VERSION 5.7 ;
  NOWIREEXTENSIONATPIN ON ;
  DIVIDERCHAR "/" ;
  BUSBITCHARS "[]" ;
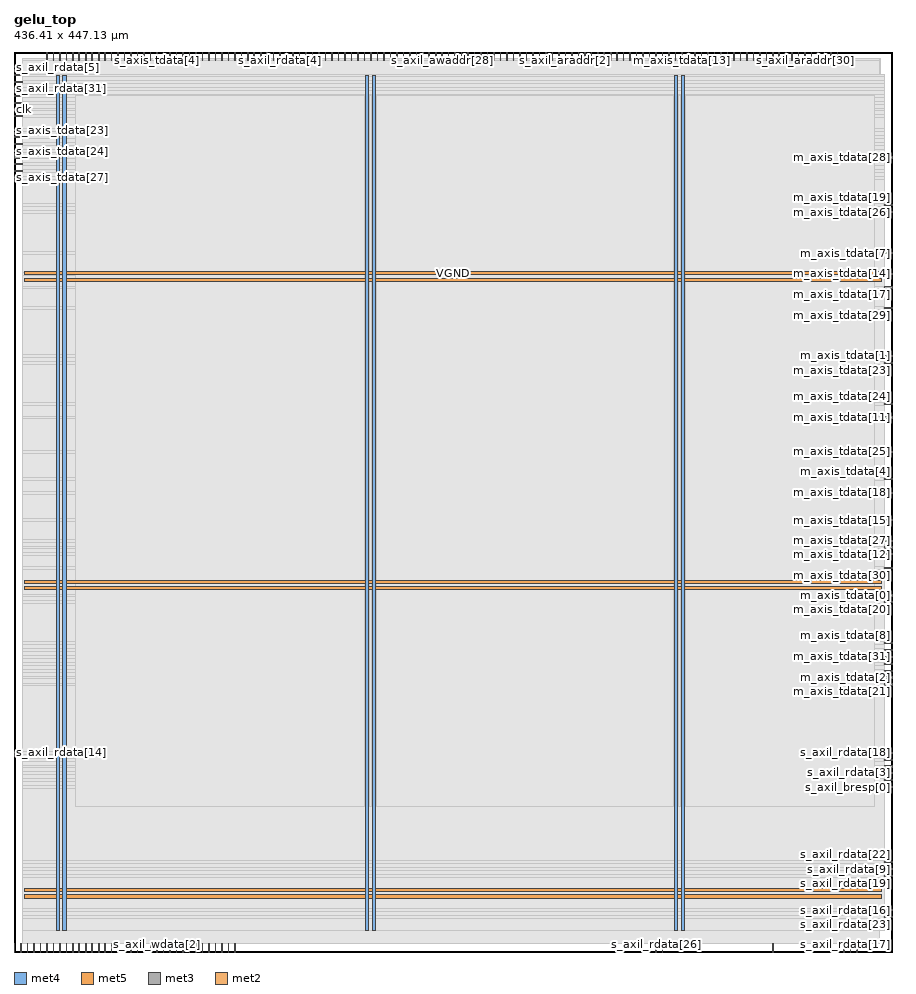
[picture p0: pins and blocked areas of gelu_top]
MACRO gelu_top
  CLASS BLOCK ;
  FOREIGN gelu_top ;
  ORIGIN 0.000 0.000 ;
  SIZE 436.410 BY 447.130 ;
  PIN VGND
    DIRECTION INOUT ;
    USE GROUND ;
    PORT
      LAYER met4 ;
        RECT 24.340 10.640 25.940 435.440 ;
    END
    PORT
      LAYER met4 ;
        RECT 177.940 10.640 179.540 435.440 ;
    END
    PORT
      LAYER met4 ;
        RECT 331.540 10.640 333.140 435.440 ;
    END
    PORT
      LAYER met5 ;
        RECT 5.280 30.030 430.800 31.630 ;
    END
    PORT
      LAYER met5 ;
        RECT 5.280 183.210 430.800 184.810 ;
    END
    PORT
      LAYER met5 ;
        RECT 5.280 336.390 430.800 337.990 ;
    END
  END VGND
  PIN VPWR
    DIRECTION INOUT ;
    USE POWER ;
    PORT
      LAYER met4 ;
        RECT 21.040 10.640 22.640 435.440 ;
    END
    PORT
      LAYER met4 ;
        RECT 174.640 10.640 176.240 435.440 ;
    END
    PORT
      LAYER met4 ;
        RECT 328.240 10.640 329.840 435.440 ;
    END
    PORT
      LAYER met5 ;
        RECT 5.280 26.730 430.800 28.330 ;
    END
    PORT
      LAYER met5 ;
        RECT 5.280 179.910 430.800 181.510 ;
    END
    PORT
      LAYER met5 ;
        RECT 5.280 333.090 430.800 334.690 ;
    END
  END VPWR
  PIN clk
    DIRECTION INPUT ;
    USE SIGNAL ;
    ANTENNAGATEAREA 0.852000 ;
    PORT
      LAYER met3 ;
        RECT 0.000 418.240 4.000 418.840 ;
    END
  END clk
  PIN m_axis_tdata[0]
    DIRECTION OUTPUT ;
    USE SIGNAL ;
    ANTENNADIFFAREA 0.445500 ;
    PORT
      LAYER met3 ;
        RECT 432.410 176.840 436.410 177.440 ;
    END
  END m_axis_tdata[0]
  PIN m_axis_tdata[10]
    DIRECTION OUTPUT ;
    USE SIGNAL ;
    ANTENNADIFFAREA 0.445500 ;
    PORT
      LAYER met2 ;
        RECT 409.030 443.130 409.310 447.130 ;
    END
  END m_axis_tdata[10]
  PIN m_axis_tdata[11]
    DIRECTION OUTPUT ;
    USE SIGNAL ;
    ANTENNADIFFAREA 0.445500 ;
    PORT
      LAYER met3 ;
        RECT 432.410 265.240 436.410 265.840 ;
    END
  END m_axis_tdata[11]
  PIN m_axis_tdata[12]
    DIRECTION OUTPUT ;
    USE SIGNAL ;
    ANTENNADIFFAREA 0.445500 ;
    PORT
      LAYER met3 ;
        RECT 432.410 197.240 436.410 197.840 ;
    END
  END m_axis_tdata[12]
  PIN m_axis_tdata[13]
    DIRECTION OUTPUT ;
    USE SIGNAL ;
    ANTENNADIFFAREA 0.445500 ;
    PORT
      LAYER met2 ;
        RECT 331.750 443.130 332.030 447.130 ;
    END
  END m_axis_tdata[13]
  PIN m_axis_tdata[14]
    DIRECTION OUTPUT ;
    USE SIGNAL ;
    ANTENNADIFFAREA 0.445500 ;
    PORT
      LAYER met3 ;
        RECT 432.410 336.640 436.410 337.240 ;
    END
  END m_axis_tdata[14]
  PIN m_axis_tdata[15]
    DIRECTION OUTPUT ;
    USE SIGNAL ;
    ANTENNADIFFAREA 0.445500 ;
    PORT
      LAYER met3 ;
        RECT 432.410 214.240 436.410 214.840 ;
    END
  END m_axis_tdata[15]
  PIN m_axis_tdata[16]
    DIRECTION OUTPUT ;
    USE SIGNAL ;
    ANTENNADIFFAREA 0.445500 ;
    PORT
      LAYER met2 ;
        RECT 322.090 443.130 322.370 447.130 ;
    END
  END m_axis_tdata[16]
  PIN m_axis_tdata[17]
    DIRECTION OUTPUT ;
    USE SIGNAL ;
    ANTENNADIFFAREA 0.445500 ;
    PORT
      LAYER met3 ;
        RECT 432.410 329.840 436.410 330.440 ;
    END
  END m_axis_tdata[17]
  PIN m_axis_tdata[18]
    DIRECTION OUTPUT ;
    USE SIGNAL ;
    ANTENNADIFFAREA 0.445500 ;
    PORT
      LAYER met3 ;
        RECT 432.410 227.840 436.410 228.440 ;
    END
  END m_axis_tdata[18]
  PIN m_axis_tdata[19]
    DIRECTION OUTPUT ;
    USE SIGNAL ;
    ANTENNADIFFAREA 0.445500 ;
    PORT
      LAYER met3 ;
        RECT 432.410 370.640 436.410 371.240 ;
    END
  END m_axis_tdata[19]
  PIN m_axis_tdata[1]
    DIRECTION OUTPUT ;
    USE SIGNAL ;
    ANTENNADIFFAREA 0.445500 ;
    PORT
      LAYER met3 ;
        RECT 432.410 295.840 436.410 296.440 ;
    END
  END m_axis_tdata[1]
  PIN m_axis_tdata[20]
    DIRECTION OUTPUT ;
    USE SIGNAL ;
    ANTENNADIFFAREA 0.445500 ;
    PORT
      LAYER met3 ;
        RECT 432.410 173.440 436.410 174.040 ;
    END
  END m_axis_tdata[20]
  PIN m_axis_tdata[21]
    DIRECTION OUTPUT ;
    USE SIGNAL ;
    ANTENNADIFFAREA 0.445500 ;
    PORT
      LAYER met3 ;
        RECT 432.410 132.640 436.410 133.240 ;
    END
  END m_axis_tdata[21]
  PIN m_axis_tdata[22]
    DIRECTION OUTPUT ;
    USE SIGNAL ;
    ANTENNADIFFAREA 0.445500 ;
    PORT
      LAYER met2 ;
        RECT 351.070 443.130 351.350 447.130 ;
    END
  END m_axis_tdata[22]
  PIN m_axis_tdata[23]
    DIRECTION OUTPUT ;
    USE SIGNAL ;
    ANTENNADIFFAREA 0.445500 ;
    PORT
      LAYER met3 ;
        RECT 432.410 292.440 436.410 293.040 ;
    END
  END m_axis_tdata[23]
  PIN m_axis_tdata[24]
    DIRECTION OUTPUT ;
    USE SIGNAL ;
    ANTENNADIFFAREA 0.445500 ;
    PORT
      LAYER met3 ;
        RECT 432.410 272.040 436.410 272.640 ;
    END
  END m_axis_tdata[24]
  PIN m_axis_tdata[25]
    DIRECTION OUTPUT ;
    USE SIGNAL ;
    ANTENNADIFFAREA 0.445500 ;
    PORT
      LAYER met3 ;
        RECT 432.410 248.240 436.410 248.840 ;
    END
  END m_axis_tdata[25]
  PIN m_axis_tdata[26]
    DIRECTION OUTPUT ;
    USE SIGNAL ;
    ANTENNADIFFAREA 0.445500 ;
    PORT
      LAYER met3 ;
        RECT 432.410 367.240 436.410 367.840 ;
    END
  END m_axis_tdata[26]
  PIN m_axis_tdata[27]
    DIRECTION OUTPUT ;
    USE SIGNAL ;
    ANTENNADIFFAREA 0.445500 ;
    PORT
      LAYER met3 ;
        RECT 432.410 200.640 436.410 201.240 ;
    END
  END m_axis_tdata[27]
  PIN m_axis_tdata[28]
    DIRECTION OUTPUT ;
    USE SIGNAL ;
    ANTENNADIFFAREA 0.445500 ;
    PORT
      LAYER met3 ;
        RECT 432.410 394.440 436.410 395.040 ;
    END
  END m_axis_tdata[28]
  PIN m_axis_tdata[29]
    DIRECTION OUTPUT ;
    USE SIGNAL ;
    ANTENNADIFFAREA 0.445500 ;
    PORT
      LAYER met3 ;
        RECT 432.410 319.640 436.410 320.240 ;
    END
  END m_axis_tdata[29]
  PIN m_axis_tdata[2]
    DIRECTION OUTPUT ;
    USE SIGNAL ;
    ANTENNADIFFAREA 0.445500 ;
    PORT
      LAYER met3 ;
        RECT 432.410 136.040 436.410 136.640 ;
    END
  END m_axis_tdata[2]
  PIN m_axis_tdata[30]
    DIRECTION OUTPUT ;
    USE SIGNAL ;
    ANTENNADIFFAREA 0.445500 ;
    PORT
      LAYER met3 ;
        RECT 432.410 190.440 436.410 191.040 ;
    END
  END m_axis_tdata[30]
  PIN m_axis_tdata[31]
    DIRECTION OUTPUT ;
    USE SIGNAL ;
    ANTENNADIFFAREA 0.445500 ;
    PORT
      LAYER met3 ;
        RECT 432.410 142.840 436.410 143.440 ;
    END
  END m_axis_tdata[31]
  PIN m_axis_tdata[3]
    DIRECTION OUTPUT ;
    USE SIGNAL ;
    ANTENNADIFFAREA 0.445500 ;
    PORT
      LAYER met3 ;
        RECT 432.410 149.640 436.410 150.240 ;
    END
  END m_axis_tdata[3]
  PIN m_axis_tdata[4]
    DIRECTION OUTPUT ;
    USE SIGNAL ;
    ANTENNADIFFAREA 0.445500 ;
    PORT
      LAYER met3 ;
        RECT 432.410 234.640 436.410 235.240 ;
    END
  END m_axis_tdata[4]
  PIN m_axis_tdata[5]
    DIRECTION OUTPUT ;
    USE SIGNAL ;
    ANTENNADIFFAREA 0.445500 ;
    PORT
      LAYER met3 ;
        RECT 432.410 204.040 436.410 204.640 ;
    END
  END m_axis_tdata[5]
  PIN m_axis_tdata[6]
    DIRECTION OUTPUT ;
    USE SIGNAL ;
    ANTENNADIFFAREA 0.445500 ;
    PORT
      LAYER met3 ;
        RECT 432.410 139.440 436.410 140.040 ;
    END
  END m_axis_tdata[6]
  PIN m_axis_tdata[7]
    DIRECTION OUTPUT ;
    USE SIGNAL ;
    ANTENNADIFFAREA 0.445500 ;
    PORT
      LAYER met3 ;
        RECT 432.410 346.840 436.410 347.440 ;
    END
  END m_axis_tdata[7]
  PIN m_axis_tdata[8]
    DIRECTION OUTPUT ;
    USE SIGNAL ;
    ANTENNADIFFAREA 0.445500 ;
    PORT
      LAYER met3 ;
        RECT 432.410 153.040 436.410 153.640 ;
    END
  END m_axis_tdata[8]
  PIN m_axis_tdata[9]
    DIRECTION OUTPUT ;
    USE SIGNAL ;
    ANTENNADIFFAREA 0.445500 ;
    PORT
      LAYER met3 ;
        RECT 432.410 146.240 436.410 146.840 ;
    END
  END m_axis_tdata[9]
  PIN m_axis_tlast
    DIRECTION OUTPUT ;
    USE SIGNAL ;
    ANTENNADIFFAREA 0.445500 ;
    PORT
      LAYER met2 ;
        RECT 357.510 443.130 357.790 447.130 ;
    END
  END m_axis_tlast
  PIN m_axis_tready
    DIRECTION INPUT ;
    USE SIGNAL ;
    ANTENNAGATEAREA 0.196500 ;
    PORT
      LAYER met2 ;
        RECT 325.310 443.130 325.590 447.130 ;
    END
  END m_axis_tready
  PIN m_axis_tuser
    DIRECTION OUTPUT ;
    USE SIGNAL ;
    ANTENNADIFFAREA 0.445500 ;
    PORT
      LAYER met2 ;
        RECT 389.710 443.130 389.990 447.130 ;
    END
  END m_axis_tuser
  PIN m_axis_tvalid
    DIRECTION OUTPUT ;
    USE SIGNAL ;
    ANTENNADIFFAREA 0.445500 ;
    PORT
      LAYER met2 ;
        RECT 270.570 443.130 270.850 447.130 ;
    END
  END m_axis_tvalid
  PIN rst
    DIRECTION INPUT ;
    USE SIGNAL ;
    ANTENNAGATEAREA 0.247500 ;
    PORT
      LAYER met3 ;
        RECT 0.000 414.840 4.000 415.440 ;
    END
  END rst
  PIN s_axil_araddr[0]
    DIRECTION INPUT ;
    USE SIGNAL ;
    ANTENNAGATEAREA 0.196500 ;
    PORT
      LAYER met2 ;
        RECT 222.270 443.130 222.550 447.130 ;
    END
  END s_axil_araddr[0]
  PIN s_axil_araddr[10]
    DIRECTION INPUT ;
    USE SIGNAL ;
    ANTENNAGATEAREA 0.196500 ;
    PORT
      LAYER met2 ;
        RECT 16.190 443.130 16.470 447.130 ;
    END
  END s_axil_araddr[10]
  PIN s_axil_araddr[11]
    DIRECTION INPUT ;
    USE SIGNAL ;
    ANTENNAGATEAREA 0.196500 ;
    PORT
      LAYER met2 ;
        RECT 141.770 443.130 142.050 447.130 ;
    END
  END s_axil_araddr[11]
  PIN s_axil_araddr[12]
    DIRECTION INPUT ;
    USE SIGNAL ;
    ANTENNAGATEAREA 0.196500 ;
    PORT
      LAYER met2 ;
        RECT 170.750 443.130 171.030 447.130 ;
    END
  END s_axil_araddr[12]
  PIN s_axil_araddr[13]
    DIRECTION INPUT ;
    USE SIGNAL ;
    ANTENNAGATEAREA 0.196500 ;
    PORT
      LAYER met2 ;
        RECT 25.850 443.130 26.130 447.130 ;
    END
  END s_axil_araddr[13]
  PIN s_axil_araddr[14]
    DIRECTION INPUT ;
    USE SIGNAL ;
    ANTENNAGATEAREA 0.196500 ;
    PORT
      LAYER met2 ;
        RECT 161.090 443.130 161.370 447.130 ;
    END
  END s_axil_araddr[14]
  PIN s_axil_araddr[15]
    DIRECTION INPUT ;
    USE SIGNAL ;
    ANTENNAGATEAREA 0.196500 ;
    PORT
      LAYER met2 ;
        RECT 138.550 443.130 138.830 447.130 ;
    END
  END s_axil_araddr[15]
  PIN s_axil_araddr[16]
    DIRECTION INPUT ;
    USE SIGNAL ;
    ANTENNAGATEAREA 0.196500 ;
    PORT
      LAYER met2 ;
        RECT 183.630 443.130 183.910 447.130 ;
    END
  END s_axil_araddr[16]
  PIN s_axil_araddr[17]
    DIRECTION INPUT ;
    USE SIGNAL ;
    ANTENNAGATEAREA 0.196500 ;
    PORT
      LAYER met2 ;
        RECT 51.610 443.130 51.890 447.130 ;
    END
  END s_axil_araddr[17]
  PIN s_axil_araddr[18]
    DIRECTION INPUT ;
    USE SIGNAL ;
    ANTENNAGATEAREA 0.196500 ;
    PORT
      LAYER met2 ;
        RECT 154.650 443.130 154.930 447.130 ;
    END
  END s_axil_araddr[18]
  PIN s_axil_araddr[19]
    DIRECTION INPUT ;
    USE SIGNAL ;
    ANTENNAGATEAREA 0.196500 ;
    PORT
      LAYER met2 ;
        RECT 151.430 443.130 151.710 447.130 ;
    END
  END s_axil_araddr[19]
  PIN s_axil_araddr[1]
    DIRECTION INPUT ;
    USE SIGNAL ;
    ANTENNAGATEAREA 0.196500 ;
    PORT
      LAYER met2 ;
        RECT 254.470 443.130 254.750 447.130 ;
    END
  END s_axil_araddr[1]
  PIN s_axil_araddr[20]
    DIRECTION INPUT ;
    USE SIGNAL ;
    ANTENNAGATEAREA 0.196500 ;
    PORT
      LAYER met2 ;
        RECT 196.510 443.130 196.790 447.130 ;
    END
  END s_axil_araddr[20]
  PIN s_axil_araddr[21]
    DIRECTION INPUT ;
    USE SIGNAL ;
    ANTENNAGATEAREA 0.196500 ;
    PORT
      LAYER met2 ;
        RECT 167.530 443.130 167.810 447.130 ;
    END
  END s_axil_araddr[21]
  PIN s_axil_araddr[22]
    DIRECTION INPUT ;
    USE SIGNAL ;
    ANTENNAGATEAREA 0.196500 ;
    PORT
      LAYER met2 ;
        RECT 376.830 443.130 377.110 447.130 ;
    END
  END s_axil_araddr[22]
  PIN s_axil_araddr[23]
    DIRECTION INPUT ;
    USE SIGNAL ;
    ANTENNAGATEAREA 0.196500 ;
    PORT
      LAYER met2 ;
        RECT 367.170 443.130 367.450 447.130 ;
    END
  END s_axil_araddr[23]
  PIN s_axil_araddr[24]
    DIRECTION INPUT ;
    USE SIGNAL ;
    ANTENNAGATEAREA 0.196500 ;
    PORT
      LAYER met2 ;
        RECT 373.610 443.130 373.890 447.130 ;
    END
  END s_axil_araddr[24]
  PIN s_axil_araddr[25]
    DIRECTION INPUT ;
    USE SIGNAL ;
    ANTENNAGATEAREA 0.126000 ;
    PORT
      LAYER met2 ;
        RECT 35.510 443.130 35.790 447.130 ;
    END
  END s_axil_araddr[25]
  PIN s_axil_araddr[26]
    DIRECTION INPUT ;
    USE SIGNAL ;
    ANTENNAGATEAREA 0.196500 ;
    PORT
      LAYER met2 ;
        RECT 186.850 443.130 187.130 447.130 ;
    END
  END s_axil_araddr[26]
  PIN s_axil_araddr[27]
    DIRECTION INPUT ;
    USE SIGNAL ;
    ANTENNAGATEAREA 0.196500 ;
    PORT
      LAYER met2 ;
        RECT 199.730 443.130 200.010 447.130 ;
    END
  END s_axil_araddr[27]
  PIN s_axil_araddr[28]
    DIRECTION INPUT ;
    USE SIGNAL ;
    ANTENNAGATEAREA 0.196500 ;
    PORT
      LAYER met2 ;
        RECT 383.270 443.130 383.550 447.130 ;
    END
  END s_axil_araddr[28]
  PIN s_axil_araddr[29]
    DIRECTION INPUT ;
    USE SIGNAL ;
    ANTENNAGATEAREA 0.196500 ;
    PORT
      LAYER met2 ;
        RECT 215.830 443.130 216.110 447.130 ;
    END
  END s_axil_araddr[29]
  PIN s_axil_araddr[2]
    DIRECTION INPUT ;
    USE SIGNAL ;
    ANTENNAGATEAREA 0.196500 ;
    PORT
      LAYER met2 ;
        RECT 273.790 443.130 274.070 447.130 ;
    END
  END s_axil_araddr[2]
  PIN s_axil_araddr[30]
    DIRECTION INPUT ;
    USE SIGNAL ;
    ANTENNAGATEAREA 0.196500 ;
    PORT
      LAYER met2 ;
        RECT 392.930 443.130 393.210 447.130 ;
    END
  END s_axil_araddr[30]
  PIN s_axil_araddr[31]
    DIRECTION INPUT ;
    USE SIGNAL ;
    ANTENNAGATEAREA 0.196500 ;
    PORT
      LAYER met2 ;
        RECT 386.490 443.130 386.770 447.130 ;
    END
  END s_axil_araddr[31]
  PIN s_axil_araddr[3]
    DIRECTION INPUT ;
    USE SIGNAL ;
    ANTENNAGATEAREA 0.196500 ;
    PORT
      LAYER met2 ;
        RECT 277.010 443.130 277.290 447.130 ;
    END
  END s_axil_araddr[3]
  PIN s_axil_araddr[4]
    DIRECTION INPUT ;
    USE SIGNAL ;
    ANTENNAGATEAREA 0.196500 ;
    PORT
      LAYER met2 ;
        RECT 128.890 443.130 129.170 447.130 ;
    END
  END s_axil_araddr[4]
  PIN s_axil_araddr[5]
    DIRECTION INPUT ;
    USE SIGNAL ;
    ANTENNAGATEAREA 0.196500 ;
    PORT
      LAYER met2 ;
        RECT 280.230 443.130 280.510 447.130 ;
    END
  END s_axil_araddr[5]
  PIN s_axil_araddr[6]
    DIRECTION INPUT ;
    USE SIGNAL ;
    ANTENNAGATEAREA 0.196500 ;
    PORT
      LAYER met2 ;
        RECT 106.350 443.130 106.630 447.130 ;
    END
  END s_axil_araddr[6]
  PIN s_axil_araddr[7]
    DIRECTION INPUT ;
    USE SIGNAL ;
    ANTENNAGATEAREA 0.196500 ;
    PORT
      LAYER met2 ;
        RECT 190.070 443.130 190.350 447.130 ;
    END
  END s_axil_araddr[7]
  PIN s_axil_araddr[8]
    DIRECTION INPUT ;
    USE SIGNAL ;
    ANTENNAGATEAREA 0.196500 ;
    PORT
      LAYER met2 ;
        RECT 193.290 443.130 193.570 447.130 ;
    END
  END s_axil_araddr[8]
  PIN s_axil_araddr[9]
    DIRECTION INPUT ;
    USE SIGNAL ;
    ANTENNAGATEAREA 0.196500 ;
    PORT
      LAYER met2 ;
        RECT 173.970 443.130 174.250 447.130 ;
    END
  END s_axil_araddr[9]
  PIN s_axil_arready
    DIRECTION OUTPUT ;
    USE SIGNAL ;
    ANTENNADIFFAREA 0.445500 ;
    PORT
      LAYER met2 ;
        RECT 251.250 443.130 251.530 447.130 ;
    END
  END s_axil_arready
  PIN s_axil_arvalid
    DIRECTION INPUT ;
    USE SIGNAL ;
    ANTENNAGATEAREA 0.196500 ;
    PORT
      LAYER met2 ;
        RECT 238.370 443.130 238.650 447.130 ;
    END
  END s_axil_arvalid
  PIN s_axil_awaddr[0]
    DIRECTION INPUT ;
    USE SIGNAL ;
    ANTENNAGATEAREA 0.196500 ;
    PORT
      LAYER met2 ;
        RECT 283.450 443.130 283.730 447.130 ;
    END
  END s_axil_awaddr[0]
  PIN s_axil_awaddr[10]
    DIRECTION INPUT ;
    USE SIGNAL ;
    ANTENNAGATEAREA 0.196500 ;
    PORT
      LAYER met2 ;
        RECT 305.990 443.130 306.270 447.130 ;
    END
  END s_axil_awaddr[10]
  PIN s_axil_awaddr[11]
    DIRECTION INPUT ;
    USE SIGNAL ;
    ANTENNAGATEAREA 0.196500 ;
    PORT
      LAYER met2 ;
        RECT 296.330 443.130 296.610 447.130 ;
    END
  END s_axil_awaddr[11]
  PIN s_axil_awaddr[12]
    DIRECTION INPUT ;
    USE SIGNAL ;
    ANTENNAGATEAREA 0.196500 ;
    PORT
      LAYER met2 ;
        RECT 219.050 443.130 219.330 447.130 ;
    END
  END s_axil_awaddr[12]
  PIN s_axil_awaddr[13]
    DIRECTION INPUT ;
    USE SIGNAL ;
    ANTENNAGATEAREA 0.196500 ;
    PORT
      LAYER met2 ;
        RECT 309.210 443.130 309.490 447.130 ;
    END
  END s_axil_awaddr[13]
  PIN s_axil_awaddr[14]
    DIRECTION INPUT ;
    USE SIGNAL ;
    ANTENNAGATEAREA 0.196500 ;
    PORT
      LAYER met2 ;
        RECT 312.430 443.130 312.710 447.130 ;
    END
  END s_axil_awaddr[14]
  PIN s_axil_awaddr[15]
    DIRECTION INPUT ;
    USE SIGNAL ;
    ANTENNAGATEAREA 0.196500 ;
    PORT
      LAYER met2 ;
        RECT 315.650 443.130 315.930 447.130 ;
    END
  END s_axil_awaddr[15]
  PIN s_axil_awaddr[16]
    DIRECTION INPUT ;
    USE SIGNAL ;
    ANTENNAGATEAREA 0.196500 ;
    PORT
      LAYER met2 ;
        RECT 318.870 443.130 319.150 447.130 ;
    END
  END s_axil_awaddr[16]
  PIN s_axil_awaddr[17]
    DIRECTION INPUT ;
    USE SIGNAL ;
    ANTENNAGATEAREA 0.196500 ;
    PORT
      LAYER met2 ;
        RECT 328.530 443.130 328.810 447.130 ;
    END
  END s_axil_awaddr[17]
  PIN s_axil_awaddr[18]
    DIRECTION INPUT ;
    USE SIGNAL ;
    ANTENNAGATEAREA 0.196500 ;
    PORT
      LAYER met2 ;
        RECT 334.970 443.130 335.250 447.130 ;
    END
  END s_axil_awaddr[18]
  PIN s_axil_awaddr[19]
    DIRECTION INPUT ;
    USE SIGNAL ;
    ANTENNAGATEAREA 0.196500 ;
    PORT
      LAYER met2 ;
        RECT 338.190 443.130 338.470 447.130 ;
    END
  END s_axil_awaddr[19]
  PIN s_axil_awaddr[1]
    DIRECTION INPUT ;
    USE SIGNAL ;
    ANTENNAGATEAREA 0.196500 ;
    PORT
      LAYER met2 ;
        RECT 241.590 443.130 241.870 447.130 ;
    END
  END s_axil_awaddr[1]
  PIN s_axil_awaddr[20]
    DIRECTION INPUT ;
    USE SIGNAL ;
    ANTENNAGATEAREA 0.196500 ;
    PORT
      LAYER met2 ;
        RECT 370.390 443.130 370.670 447.130 ;
    END
  END s_axil_awaddr[20]
  PIN s_axil_awaddr[21]
    DIRECTION INPUT ;
    USE SIGNAL ;
    ANTENNAGATEAREA 0.196500 ;
    PORT
      LAYER met2 ;
        RECT 341.410 443.130 341.690 447.130 ;
    END
  END s_axil_awaddr[21]
  PIN s_axil_awaddr[22]
    DIRECTION INPUT ;
    USE SIGNAL ;
    ANTENNAGATEAREA 0.126000 ;
    PORT
      LAYER met2 ;
        RECT 22.630 443.130 22.910 447.130 ;
    END
  END s_axil_awaddr[22]
  PIN s_axil_awaddr[23]
    DIRECTION INPUT ;
    USE SIGNAL ;
    ANTENNAGATEAREA 0.196500 ;
    PORT
      LAYER met2 ;
        RECT 209.390 443.130 209.670 447.130 ;
    END
  END s_axil_awaddr[23]
  PIN s_axil_awaddr[24]
    DIRECTION INPUT ;
    USE SIGNAL ;
    ANTENNAGATEAREA 0.196500 ;
    PORT
      LAYER met2 ;
        RECT 177.190 443.130 177.470 447.130 ;
    END
  END s_axil_awaddr[24]
  PIN s_axil_awaddr[25]
    DIRECTION INPUT ;
    USE SIGNAL ;
    ANTENNAGATEAREA 0.196500 ;
    PORT
      LAYER met2 ;
        RECT 206.170 443.130 206.450 447.130 ;
    END
  END s_axil_awaddr[25]
  PIN s_axil_awaddr[26]
    DIRECTION INPUT ;
    USE SIGNAL ;
    ANTENNAGATEAREA 0.213000 ;
    PORT
      LAYER met2 ;
        RECT 19.410 443.130 19.690 447.130 ;
    END
  END s_axil_awaddr[26]
  PIN s_axil_awaddr[27]
    DIRECTION INPUT ;
    USE SIGNAL ;
    ANTENNAGATEAREA 0.126000 ;
    PORT
      LAYER met2 ;
        RECT 396.150 443.130 396.430 447.130 ;
    END
  END s_axil_awaddr[27]
  PIN s_axil_awaddr[28]
    DIRECTION INPUT ;
    USE SIGNAL ;
    ANTENNAGATEAREA 0.196500 ;
    PORT
      LAYER met2 ;
        RECT 212.610 443.130 212.890 447.130 ;
    END
  END s_axil_awaddr[28]
  PIN s_axil_awaddr[29]
    DIRECTION INPUT ;
    USE SIGNAL ;
    ANTENNAGATEAREA 0.213000 ;
    PORT
      LAYER met2 ;
        RECT 402.590 443.130 402.870 447.130 ;
    END
  END s_axil_awaddr[29]
  PIN s_axil_awaddr[2]
    DIRECTION INPUT ;
    USE SIGNAL ;
    ANTENNAGATEAREA 0.196500 ;
    PORT
      LAYER met2 ;
        RECT 302.770 443.130 303.050 447.130 ;
    END
  END s_axil_awaddr[2]
  PIN s_axil_awaddr[30]
    DIRECTION INPUT ;
    USE SIGNAL ;
    ANTENNAGATEAREA 0.196500 ;
    PORT
      LAYER met2 ;
        RECT 380.050 443.130 380.330 447.130 ;
    END
  END s_axil_awaddr[30]
  PIN s_axil_awaddr[31]
    DIRECTION INPUT ;
    USE SIGNAL ;
    ANTENNAGATEAREA 0.196500 ;
    PORT
      LAYER met2 ;
        RECT 399.370 443.130 399.650 447.130 ;
    END
  END s_axil_awaddr[31]
  PIN s_axil_awaddr[3]
    DIRECTION INPUT ;
    USE SIGNAL ;
    ANTENNAGATEAREA 0.196500 ;
    PORT
      LAYER met2 ;
        RECT 286.670 443.130 286.950 447.130 ;
    END
  END s_axil_awaddr[3]
  PIN s_axil_awaddr[4]
    DIRECTION INPUT ;
    USE SIGNAL ;
    ANTENNAGATEAREA 0.196500 ;
    PORT
      LAYER met2 ;
        RECT 344.630 443.130 344.910 447.130 ;
    END
  END s_axil_awaddr[4]
  PIN s_axil_awaddr[5]
    DIRECTION INPUT ;
    USE SIGNAL ;
    ANTENNAGATEAREA 0.196500 ;
    PORT
      LAYER met2 ;
        RECT 299.550 443.130 299.830 447.130 ;
    END
  END s_axil_awaddr[5]
  PIN s_axil_awaddr[6]
    DIRECTION INPUT ;
    USE SIGNAL ;
    ANTENNAGATEAREA 0.196500 ;
    PORT
      LAYER met2 ;
        RECT 347.850 443.130 348.130 447.130 ;
    END
  END s_axil_awaddr[6]
  PIN s_axil_awaddr[7]
    DIRECTION INPUT ;
    USE SIGNAL ;
    ANTENNAGATEAREA 0.196500 ;
    PORT
      LAYER met2 ;
        RECT 360.730 443.130 361.010 447.130 ;
    END
  END s_axil_awaddr[7]
  PIN s_axil_awaddr[8]
    DIRECTION INPUT ;
    USE SIGNAL ;
    ANTENNAGATEAREA 0.196500 ;
    PORT
      LAYER met2 ;
        RECT 354.290 443.130 354.570 447.130 ;
    END
  END s_axil_awaddr[8]
  PIN s_axil_awaddr[9]
    DIRECTION INPUT ;
    USE SIGNAL ;
    ANTENNAGATEAREA 0.196500 ;
    PORT
      LAYER met2 ;
        RECT 363.950 443.130 364.230 447.130 ;
    END
  END s_axil_awaddr[9]
  PIN s_axil_awready
    DIRECTION OUTPUT ;
    USE SIGNAL ;
    ANTENNADIFFAREA 0.445500 ;
    PORT
      LAYER met2 ;
        RECT 122.450 443.130 122.730 447.130 ;
    END
  END s_axil_awready
  PIN s_axil_awvalid
    DIRECTION INPUT ;
    USE SIGNAL ;
    ANTENNAGATEAREA 0.196500 ;
    PORT
      LAYER met2 ;
        RECT 148.210 443.130 148.490 447.130 ;
    END
  END s_axil_awvalid
  PIN s_axil_bready
    DIRECTION INPUT ;
    USE SIGNAL ;
    ANTENNAGATEAREA 0.196500 ;
    PORT
      LAYER met2 ;
        RECT 180.410 443.130 180.690 447.130 ;
    END
  END s_axil_bready
  PIN s_axil_bresp[0]
    DIRECTION OUTPUT ;
    USE SIGNAL ;
    PORT
      LAYER met3 ;
        RECT 432.410 81.640 436.410 82.240 ;
    END
  END s_axil_bresp[0]
  PIN s_axil_bresp[1]
    DIRECTION OUTPUT ;
    USE SIGNAL ;
    PORT
      LAYER met2 ;
        RECT 409.030 0.000 409.310 4.000 ;
    END
  END s_axil_bresp[1]
  PIN s_axil_bvalid
    DIRECTION OUTPUT ;
    USE SIGNAL ;
    ANTENNADIFFAREA 0.445500 ;
    PORT
      LAYER met2 ;
        RECT 157.870 443.130 158.150 447.130 ;
    END
  END s_axil_bvalid
  PIN s_axil_rdata[0]
    DIRECTION OUTPUT ;
    USE SIGNAL ;
    ANTENNADIFFAREA 0.445500 ;
    PORT
      LAYER met2 ;
        RECT 244.810 443.130 245.090 447.130 ;
    END
  END s_axil_rdata[0]
  PIN s_axil_rdata[10]
    DIRECTION OUTPUT ;
    USE SIGNAL ;
    PORT
      LAYER met3 ;
        RECT 0.000 421.640 4.000 422.240 ;
    END
  END s_axil_rdata[10]
  PIN s_axil_rdata[11]
    DIRECTION OUTPUT ;
    USE SIGNAL ;
    PORT
      LAYER met2 ;
        RECT 418.690 0.000 418.970 4.000 ;
    END
  END s_axil_rdata[11]
  PIN s_axil_rdata[12]
    DIRECTION OUTPUT ;
    USE SIGNAL ;
    PORT
      LAYER met2 ;
        RECT 267.350 443.130 267.630 447.130 ;
    END
  END s_axil_rdata[12]
  PIN s_axil_rdata[13]
    DIRECTION OUTPUT ;
    USE SIGNAL ;
    PORT
      LAYER met2 ;
        RECT 228.710 443.130 228.990 447.130 ;
    END
  END s_axil_rdata[13]
  PIN s_axil_rdata[14]
    DIRECTION OUTPUT ;
    USE SIGNAL ;
    PORT
      LAYER met3 ;
        RECT 0.000 98.640 4.000 99.240 ;
    END
  END s_axil_rdata[14]
  PIN s_axil_rdata[15]
    DIRECTION OUTPUT ;
    USE SIGNAL ;
    PORT
      LAYER met2 ;
        RECT 293.110 443.130 293.390 447.130 ;
    END
  END s_axil_rdata[15]
  PIN s_axil_rdata[16]
    DIRECTION OUTPUT ;
    USE SIGNAL ;
    PORT
      LAYER met3 ;
        RECT 432.410 20.440 436.410 21.040 ;
    END
  END s_axil_rdata[16]
  PIN s_axil_rdata[17]
    DIRECTION OUTPUT ;
    USE SIGNAL ;
    PORT
      LAYER met2 ;
        RECT 415.470 0.000 415.750 4.000 ;
    END
  END s_axil_rdata[17]
  PIN s_axil_rdata[18]
    DIRECTION OUTPUT ;
    USE SIGNAL ;
    PORT
      LAYER met3 ;
        RECT 432.410 98.640 436.410 99.240 ;
    END
  END s_axil_rdata[18]
  PIN s_axil_rdata[19]
    DIRECTION OUTPUT ;
    USE SIGNAL ;
    PORT
      LAYER met3 ;
        RECT 432.410 37.440 436.410 38.040 ;
    END
  END s_axil_rdata[19]
  PIN s_axil_rdata[1]
    DIRECTION OUTPUT ;
    USE SIGNAL ;
    PORT
      LAYER met3 ;
        RECT 0.000 431.840 4.000 432.440 ;
    END
  END s_axil_rdata[1]
  PIN s_axil_rdata[20]
    DIRECTION OUTPUT ;
    USE SIGNAL ;
    PORT
      LAYER met2 ;
        RECT 164.310 443.130 164.590 447.130 ;
    END
  END s_axil_rdata[20]
  PIN s_axil_rdata[21]
    DIRECTION OUTPUT ;
    USE SIGNAL ;
    PORT
      LAYER met2 ;
        RECT 376.830 0.000 377.110 4.000 ;
    END
  END s_axil_rdata[21]
  PIN s_axil_rdata[22]
    DIRECTION OUTPUT ;
    USE SIGNAL ;
    PORT
      LAYER met3 ;
        RECT 432.410 44.240 436.410 44.840 ;
    END
  END s_axil_rdata[22]
  PIN s_axil_rdata[23]
    DIRECTION OUTPUT ;
    USE SIGNAL ;
    PORT
      LAYER met3 ;
        RECT 432.410 17.040 436.410 17.640 ;
    END
  END s_axil_rdata[23]
  PIN s_axil_rdata[24]
    DIRECTION OUTPUT ;
    USE SIGNAL ;
    PORT
      LAYER met2 ;
        RECT 412.250 0.000 412.530 4.000 ;
    END
  END s_axil_rdata[24]
  PIN s_axil_rdata[25]
    DIRECTION OUTPUT ;
    USE SIGNAL ;
    PORT
      LAYER met2 ;
        RECT 77.370 443.130 77.650 447.130 ;
    END
  END s_axil_rdata[25]
  PIN s_axil_rdata[26]
    DIRECTION OUTPUT ;
    USE SIGNAL ;
    PORT
      LAYER met2 ;
        RECT 318.870 0.000 319.150 4.000 ;
    END
  END s_axil_rdata[26]
  PIN s_axil_rdata[27]
    DIRECTION OUTPUT ;
    USE SIGNAL ;
    PORT
      LAYER met3 ;
        RECT 0.000 428.440 4.000 429.040 ;
    END
  END s_axil_rdata[27]
  PIN s_axil_rdata[28]
    DIRECTION OUTPUT ;
    USE SIGNAL ;
    PORT
      LAYER met3 ;
        RECT 432.410 95.240 436.410 95.840 ;
    END
  END s_axil_rdata[28]
  PIN s_axil_rdata[29]
    DIRECTION OUTPUT ;
    USE SIGNAL ;
    PORT
      LAYER met2 ;
        RECT 322.090 0.000 322.370 4.000 ;
    END
  END s_axil_rdata[29]
  PIN s_axil_rdata[2]
    DIRECTION OUTPUT ;
    USE SIGNAL ;
    PORT
      LAYER met3 ;
        RECT 432.410 91.840 436.410 92.440 ;
    END
  END s_axil_rdata[2]
  PIN s_axil_rdata[30]
    DIRECTION OUTPUT ;
    USE SIGNAL ;
    PORT
      LAYER met2 ;
        RECT 135.330 443.130 135.610 447.130 ;
    END
  END s_axil_rdata[30]
  PIN s_axil_rdata[31]
    DIRECTION OUTPUT ;
    USE SIGNAL ;
    PORT
      LAYER met3 ;
        RECT 0.000 425.040 4.000 425.640 ;
    END
  END s_axil_rdata[31]
  PIN s_axil_rdata[3]
    DIRECTION OUTPUT ;
    USE SIGNAL ;
    PORT
      LAYER met3 ;
        RECT 432.410 85.040 436.410 85.640 ;
    END
  END s_axil_rdata[3]
  PIN s_axil_rdata[4]
    DIRECTION OUTPUT ;
    USE SIGNAL ;
    PORT
      LAYER met2 ;
        RECT 132.110 443.130 132.390 447.130 ;
    END
  END s_axil_rdata[4]
  PIN s_axil_rdata[5]
    DIRECTION OUTPUT ;
    USE SIGNAL ;
    PORT
      LAYER met3 ;
        RECT 0.000 435.240 4.000 435.840 ;
    END
  END s_axil_rdata[5]
  PIN s_axil_rdata[6]
    DIRECTION OUTPUT ;
    USE SIGNAL ;
    PORT
      LAYER met2 ;
        RECT 144.990 443.130 145.270 447.130 ;
    END
  END s_axil_rdata[6]
  PIN s_axil_rdata[7]
    DIRECTION OUTPUT ;
    USE SIGNAL ;
    PORT
      LAYER met3 ;
        RECT 432.410 88.440 436.410 89.040 ;
    END
  END s_axil_rdata[7]
  PIN s_axil_rdata[8]
    DIRECTION OUTPUT ;
    USE SIGNAL ;
    PORT
      LAYER met2 ;
        RECT 67.710 443.130 67.990 447.130 ;
    END
  END s_axil_rdata[8]
  PIN s_axil_rdata[9]
    DIRECTION OUTPUT ;
    USE SIGNAL ;
    PORT
      LAYER met3 ;
        RECT 432.410 40.840 436.410 41.440 ;
    END
  END s_axil_rdata[9]
  PIN s_axil_rready
    DIRECTION INPUT ;
    USE SIGNAL ;
    ANTENNAGATEAREA 0.196500 ;
    PORT
      LAYER met2 ;
        RECT 225.490 443.130 225.770 447.130 ;
    END
  END s_axil_rready
  PIN s_axil_rresp[0]
    DIRECTION OUTPUT ;
    USE SIGNAL ;
    PORT
      LAYER met2 ;
        RECT 231.930 443.130 232.210 447.130 ;
    END
  END s_axil_rresp[0]
  PIN s_axil_rresp[1]
    DIRECTION OUTPUT ;
    USE SIGNAL ;
    PORT
      LAYER met2 ;
        RECT 58.050 0.000 58.330 4.000 ;
    END
  END s_axil_rresp[1]
  PIN s_axil_rvalid
    DIRECTION OUTPUT ;
    USE SIGNAL ;
    ANTENNADIFFAREA 0.445500 ;
    PORT
      LAYER met2 ;
        RECT 235.150 443.130 235.430 447.130 ;
    END
  END s_axil_rvalid
  PIN s_axil_wdata[0]
    DIRECTION INPUT ;
    USE SIGNAL ;
    ANTENNAGATEAREA 0.196500 ;
    PORT
      LAYER met2 ;
        RECT 289.890 443.130 290.170 447.130 ;
    END
  END s_axil_wdata[0]
  PIN s_axil_wdata[10]
    DIRECTION INPUT ;
    USE SIGNAL ;
    PORT
      LAYER met2 ;
        RECT 0.090 0.000 0.370 4.000 ;
    END
  END s_axil_wdata[10]
  PIN s_axil_wdata[11]
    DIRECTION INPUT ;
    USE SIGNAL ;
    PORT
      LAYER met2 ;
        RECT 3.310 0.000 3.590 4.000 ;
    END
  END s_axil_wdata[11]
  PIN s_axil_wdata[12]
    DIRECTION INPUT ;
    USE SIGNAL ;
    PORT
      LAYER met2 ;
        RECT 6.530 0.000 6.810 4.000 ;
    END
  END s_axil_wdata[12]
  PIN s_axil_wdata[13]
    DIRECTION INPUT ;
    USE SIGNAL ;
    PORT
      LAYER met2 ;
        RECT 9.750 0.000 10.030 4.000 ;
    END
  END s_axil_wdata[13]
  PIN s_axil_wdata[14]
    DIRECTION INPUT ;
    USE SIGNAL ;
    PORT
      LAYER met2 ;
        RECT 12.970 0.000 13.250 4.000 ;
    END
  END s_axil_wdata[14]
  PIN s_axil_wdata[15]
    DIRECTION INPUT ;
    USE SIGNAL ;
    PORT
      LAYER met2 ;
        RECT 16.190 0.000 16.470 4.000 ;
    END
  END s_axil_wdata[15]
  PIN s_axil_wdata[16]
    DIRECTION INPUT ;
    USE SIGNAL ;
    PORT
      LAYER met2 ;
        RECT 19.410 0.000 19.690 4.000 ;
    END
  END s_axil_wdata[16]
  PIN s_axil_wdata[17]
    DIRECTION INPUT ;
    USE SIGNAL ;
    PORT
      LAYER met2 ;
        RECT 22.630 0.000 22.910 4.000 ;
    END
  END s_axil_wdata[17]
  PIN s_axil_wdata[18]
    DIRECTION INPUT ;
    USE SIGNAL ;
    PORT
      LAYER met2 ;
        RECT 25.850 0.000 26.130 4.000 ;
    END
  END s_axil_wdata[18]
  PIN s_axil_wdata[19]
    DIRECTION INPUT ;
    USE SIGNAL ;
    PORT
      LAYER met2 ;
        RECT 29.070 0.000 29.350 4.000 ;
    END
  END s_axil_wdata[19]
  PIN s_axil_wdata[1]
    DIRECTION INPUT ;
    USE SIGNAL ;
    PORT
      LAYER met2 ;
        RECT 32.290 0.000 32.570 4.000 ;
    END
  END s_axil_wdata[1]
  PIN s_axil_wdata[20]
    DIRECTION INPUT ;
    USE SIGNAL ;
    PORT
      LAYER met2 ;
        RECT 35.510 0.000 35.790 4.000 ;
    END
  END s_axil_wdata[20]
  PIN s_axil_wdata[21]
    DIRECTION INPUT ;
    USE SIGNAL ;
    PORT
      LAYER met2 ;
        RECT 38.730 0.000 39.010 4.000 ;
    END
  END s_axil_wdata[21]
  PIN s_axil_wdata[22]
    DIRECTION INPUT ;
    USE SIGNAL ;
    PORT
      LAYER met2 ;
        RECT 41.950 0.000 42.230 4.000 ;
    END
  END s_axil_wdata[22]
  PIN s_axil_wdata[23]
    DIRECTION INPUT ;
    USE SIGNAL ;
    PORT
      LAYER met2 ;
        RECT 45.170 0.000 45.450 4.000 ;
    END
  END s_axil_wdata[23]
  PIN s_axil_wdata[24]
    DIRECTION INPUT ;
    USE SIGNAL ;
    PORT
      LAYER met2 ;
        RECT 48.390 0.000 48.670 4.000 ;
    END
  END s_axil_wdata[24]
  PIN s_axil_wdata[25]
    DIRECTION INPUT ;
    USE SIGNAL ;
    PORT
      LAYER met2 ;
        RECT 51.610 0.000 51.890 4.000 ;
    END
  END s_axil_wdata[25]
  PIN s_axil_wdata[26]
    DIRECTION INPUT ;
    USE SIGNAL ;
    PORT
      LAYER met2 ;
        RECT 54.830 0.000 55.110 4.000 ;
    END
  END s_axil_wdata[26]
  PIN s_axil_wdata[27]
    DIRECTION INPUT ;
    USE SIGNAL ;
    PORT
      LAYER met2 ;
        RECT 61.270 0.000 61.550 4.000 ;
    END
  END s_axil_wdata[27]
  PIN s_axil_wdata[28]
    DIRECTION INPUT ;
    USE SIGNAL ;
    PORT
      LAYER met2 ;
        RECT 64.490 0.000 64.770 4.000 ;
    END
  END s_axil_wdata[28]
  PIN s_axil_wdata[29]
    DIRECTION INPUT ;
    USE SIGNAL ;
    PORT
      LAYER met2 ;
        RECT 67.710 0.000 67.990 4.000 ;
    END
  END s_axil_wdata[29]
  PIN s_axil_wdata[2]
    DIRECTION INPUT ;
    USE SIGNAL ;
    PORT
      LAYER met2 ;
        RECT 70.930 0.000 71.210 4.000 ;
    END
  END s_axil_wdata[2]
  PIN s_axil_wdata[30]
    DIRECTION INPUT ;
    USE SIGNAL ;
    PORT
      LAYER met2 ;
        RECT 74.150 0.000 74.430 4.000 ;
    END
  END s_axil_wdata[30]
  PIN s_axil_wdata[31]
    DIRECTION INPUT ;
    USE SIGNAL ;
    PORT
      LAYER met2 ;
        RECT 77.370 0.000 77.650 4.000 ;
    END
  END s_axil_wdata[31]
  PIN s_axil_wdata[3]
    DIRECTION INPUT ;
    USE SIGNAL ;
    PORT
      LAYER met2 ;
        RECT 80.590 0.000 80.870 4.000 ;
    END
  END s_axil_wdata[3]
  PIN s_axil_wdata[4]
    DIRECTION INPUT ;
    USE SIGNAL ;
    PORT
      LAYER met2 ;
        RECT 83.810 0.000 84.090 4.000 ;
    END
  END s_axil_wdata[4]
  PIN s_axil_wdata[5]
    DIRECTION INPUT ;
    USE SIGNAL ;
    PORT
      LAYER met2 ;
        RECT 87.030 0.000 87.310 4.000 ;
    END
  END s_axil_wdata[5]
  PIN s_axil_wdata[6]
    DIRECTION INPUT ;
    USE SIGNAL ;
    PORT
      LAYER met2 ;
        RECT 90.250 0.000 90.530 4.000 ;
    END
  END s_axil_wdata[6]
  PIN s_axil_wdata[7]
    DIRECTION INPUT ;
    USE SIGNAL ;
    PORT
      LAYER met2 ;
        RECT 93.470 0.000 93.750 4.000 ;
    END
  END s_axil_wdata[7]
  PIN s_axil_wdata[8]
    DIRECTION INPUT ;
    USE SIGNAL ;
    PORT
      LAYER met2 ;
        RECT 96.690 0.000 96.970 4.000 ;
    END
  END s_axil_wdata[8]
  PIN s_axil_wdata[9]
    DIRECTION INPUT ;
    USE SIGNAL ;
    PORT
      LAYER met2 ;
        RECT 99.910 0.000 100.190 4.000 ;
    END
  END s_axil_wdata[9]
  PIN s_axil_wready
    DIRECTION OUTPUT ;
    USE SIGNAL ;
    ANTENNADIFFAREA 0.445500 ;
    PORT
      LAYER met2 ;
        RECT 54.830 443.130 55.110 447.130 ;
    END
  END s_axil_wready
  PIN s_axil_wstrb[0]
    DIRECTION INPUT ;
    USE SIGNAL ;
    ANTENNAGATEAREA 0.196500 ;
    PORT
      LAYER met2 ;
        RECT 405.810 443.130 406.090 447.130 ;
    END
  END s_axil_wstrb[0]
  PIN s_axil_wstrb[1]
    DIRECTION INPUT ;
    USE SIGNAL ;
    PORT
      LAYER met2 ;
        RECT 103.130 0.000 103.410 4.000 ;
    END
  END s_axil_wstrb[1]
  PIN s_axil_wstrb[2]
    DIRECTION INPUT ;
    USE SIGNAL ;
    PORT
      LAYER met2 ;
        RECT 106.350 0.000 106.630 4.000 ;
    END
  END s_axil_wstrb[2]
  PIN s_axil_wstrb[3]
    DIRECTION INPUT ;
    USE SIGNAL ;
    PORT
      LAYER met2 ;
        RECT 109.570 0.000 109.850 4.000 ;
    END
  END s_axil_wstrb[3]
  PIN s_axil_wvalid
    DIRECTION INPUT ;
    USE SIGNAL ;
    ANTENNAGATEAREA 0.196500 ;
    PORT
      LAYER met2 ;
        RECT 202.950 443.130 203.230 447.130 ;
    END
  END s_axil_wvalid
  PIN s_axis_tdata[0]
    DIRECTION INPUT ;
    USE SIGNAL ;
    ANTENNAGATEAREA 0.196500 ;
    PORT
      LAYER met2 ;
        RECT 41.950 443.130 42.230 447.130 ;
    END
  END s_axis_tdata[0]
  PIN s_axis_tdata[10]
    DIRECTION INPUT ;
    USE SIGNAL ;
    ANTENNAGATEAREA 0.196500 ;
    PORT
      LAYER met2 ;
        RECT 87.030 443.130 87.310 447.130 ;
    END
  END s_axis_tdata[10]
  PIN s_axis_tdata[11]
    DIRECTION INPUT ;
    USE SIGNAL ;
    ANTENNAGATEAREA 0.196500 ;
    PORT
      LAYER met2 ;
        RECT 93.470 443.130 93.750 447.130 ;
    END
  END s_axis_tdata[11]
  PIN s_axis_tdata[12]
    DIRECTION INPUT ;
    USE SIGNAL ;
    ANTENNAGATEAREA 0.196500 ;
    PORT
      LAYER met2 ;
        RECT 83.810 443.130 84.090 447.130 ;
    END
  END s_axis_tdata[12]
  PIN s_axis_tdata[13]
    DIRECTION INPUT ;
    USE SIGNAL ;
    ANTENNAGATEAREA 0.196500 ;
    PORT
      LAYER met2 ;
        RECT 80.590 443.130 80.870 447.130 ;
    END
  END s_axis_tdata[13]
  PIN s_axis_tdata[14]
    DIRECTION INPUT ;
    USE SIGNAL ;
    ANTENNAGATEAREA 0.196500 ;
    PORT
      LAYER met2 ;
        RECT 74.150 443.130 74.430 447.130 ;
    END
  END s_axis_tdata[14]
  PIN s_axis_tdata[15]
    DIRECTION INPUT ;
    USE SIGNAL ;
    ANTENNAGATEAREA 0.196500 ;
    PORT
      LAYER met2 ;
        RECT 38.730 443.130 39.010 447.130 ;
    END
  END s_axis_tdata[15]
  PIN s_axis_tdata[16]
    DIRECTION INPUT ;
    USE SIGNAL ;
    ANTENNAGATEAREA 0.196500 ;
    PORT
      LAYER met2 ;
        RECT 29.070 443.130 29.350 447.130 ;
    END
  END s_axis_tdata[16]
  PIN s_axis_tdata[17]
    DIRECTION INPUT ;
    USE SIGNAL ;
    ANTENNAGATEAREA 0.196500 ;
    PORT
      LAYER met2 ;
        RECT 58.050 443.130 58.330 447.130 ;
    END
  END s_axis_tdata[17]
  PIN s_axis_tdata[18]
    DIRECTION INPUT ;
    USE SIGNAL ;
    ANTENNAGATEAREA 0.196500 ;
    PORT
      LAYER met2 ;
        RECT 61.270 443.130 61.550 447.130 ;
    END
  END s_axis_tdata[18]
  PIN s_axis_tdata[19]
    DIRECTION INPUT ;
    USE SIGNAL ;
    ANTENNAGATEAREA 0.196500 ;
    PORT
      LAYER met2 ;
        RECT 64.490 443.130 64.770 447.130 ;
    END
  END s_axis_tdata[19]
  PIN s_axis_tdata[1]
    DIRECTION INPUT ;
    USE SIGNAL ;
    ANTENNAGATEAREA 0.196500 ;
    PORT
      LAYER met2 ;
        RECT 45.170 443.130 45.450 447.130 ;
    END
  END s_axis_tdata[1]
  PIN s_axis_tdata[20]
    DIRECTION INPUT ;
    USE SIGNAL ;
    ANTENNAGATEAREA 0.196500 ;
    PORT
      LAYER met2 ;
        RECT 112.790 443.130 113.070 447.130 ;
    END
  END s_axis_tdata[20]
  PIN s_axis_tdata[21]
    DIRECTION INPUT ;
    USE SIGNAL ;
    ANTENNAGATEAREA 0.196500 ;
    PORT
      LAYER met2 ;
        RECT 103.130 443.130 103.410 447.130 ;
    END
  END s_axis_tdata[21]
  PIN s_axis_tdata[22]
    DIRECTION INPUT ;
    USE SIGNAL ;
    ANTENNAGATEAREA 0.196500 ;
    PORT
      LAYER met2 ;
        RECT 116.010 443.130 116.290 447.130 ;
    END
  END s_axis_tdata[22]
  PIN s_axis_tdata[23]
    DIRECTION INPUT ;
    USE SIGNAL ;
    ANTENNAGATEAREA 0.196500 ;
    PORT
      LAYER met3 ;
        RECT 0.000 408.040 4.000 408.640 ;
    END
  END s_axis_tdata[23]
  PIN s_axis_tdata[24]
    DIRECTION INPUT ;
    USE SIGNAL ;
    ANTENNAGATEAREA 0.196500 ;
    PORT
      LAYER met3 ;
        RECT 0.000 401.240 4.000 401.840 ;
    END
  END s_axis_tdata[24]
  PIN s_axis_tdata[25]
    DIRECTION INPUT ;
    USE SIGNAL ;
    ANTENNAGATEAREA 0.196500 ;
    PORT
      LAYER met3 ;
        RECT 0.000 404.640 4.000 405.240 ;
    END
  END s_axis_tdata[25]
  PIN s_axis_tdata[26]
    DIRECTION INPUT ;
    USE SIGNAL ;
    ANTENNAGATEAREA 0.196500 ;
    PORT
      LAYER met3 ;
        RECT 0.000 397.840 4.000 398.440 ;
    END
  END s_axis_tdata[26]
  PIN s_axis_tdata[27]
    DIRECTION INPUT ;
    USE SIGNAL ;
    ANTENNAGATEAREA 0.196500 ;
    PORT
      LAYER met3 ;
        RECT 0.000 384.240 4.000 384.840 ;
    END
  END s_axis_tdata[27]
  PIN s_axis_tdata[28]
    DIRECTION INPUT ;
    USE SIGNAL ;
    ANTENNAGATEAREA 0.196500 ;
    PORT
      LAYER met3 ;
        RECT 0.000 391.040 4.000 391.640 ;
    END
  END s_axis_tdata[28]
  PIN s_axis_tdata[29]
    DIRECTION INPUT ;
    USE SIGNAL ;
    ANTENNAGATEAREA 0.196500 ;
    PORT
      LAYER met3 ;
        RECT 0.000 387.640 4.000 388.240 ;
    END
  END s_axis_tdata[29]
  PIN s_axis_tdata[2]
    DIRECTION INPUT ;
    USE SIGNAL ;
    ANTENNAGATEAREA 0.196500 ;
    PORT
      LAYER met2 ;
        RECT 32.290 443.130 32.570 447.130 ;
    END
  END s_axis_tdata[2]
  PIN s_axis_tdata[30]
    DIRECTION INPUT ;
    USE SIGNAL ;
    ANTENNAGATEAREA 0.196500 ;
    PORT
      LAYER met3 ;
        RECT 0.000 394.440 4.000 395.040 ;
    END
  END s_axis_tdata[30]
  PIN s_axis_tdata[31]
    DIRECTION INPUT ;
    USE SIGNAL ;
    ANTENNAGATEAREA 0.196500 ;
    PORT
      LAYER met2 ;
        RECT 125.670 443.130 125.950 447.130 ;
    END
  END s_axis_tdata[31]
  PIN s_axis_tdata[3]
    DIRECTION INPUT ;
    USE SIGNAL ;
    ANTENNAGATEAREA 0.196500 ;
    PORT
      LAYER met2 ;
        RECT 48.390 443.130 48.670 447.130 ;
    END
  END s_axis_tdata[3]
  PIN s_axis_tdata[4]
    DIRECTION INPUT ;
    USE SIGNAL ;
    ANTENNAGATEAREA 0.196500 ;
    PORT
      LAYER met2 ;
        RECT 70.930 443.130 71.210 447.130 ;
    END
  END s_axis_tdata[4]
  PIN s_axis_tdata[5]
    DIRECTION INPUT ;
    USE SIGNAL ;
    ANTENNAGATEAREA 0.196500 ;
    PORT
      LAYER met2 ;
        RECT 119.230 443.130 119.510 447.130 ;
    END
  END s_axis_tdata[5]
  PIN s_axis_tdata[6]
    DIRECTION INPUT ;
    USE SIGNAL ;
    ANTENNAGATEAREA 0.196500 ;
    PORT
      LAYER met2 ;
        RECT 109.570 443.130 109.850 447.130 ;
    END
  END s_axis_tdata[6]
  PIN s_axis_tdata[7]
    DIRECTION INPUT ;
    USE SIGNAL ;
    ANTENNAGATEAREA 0.196500 ;
    PORT
      LAYER met2 ;
        RECT 96.690 443.130 96.970 447.130 ;
    END
  END s_axis_tdata[7]
  PIN s_axis_tdata[8]
    DIRECTION INPUT ;
    USE SIGNAL ;
    ANTENNAGATEAREA 0.196500 ;
    PORT
      LAYER met2 ;
        RECT 99.910 443.130 100.190 447.130 ;
    END
  END s_axis_tdata[8]
  PIN s_axis_tdata[9]
    DIRECTION INPUT ;
    USE SIGNAL ;
    ANTENNAGATEAREA 0.196500 ;
    PORT
      LAYER met2 ;
        RECT 90.250 443.130 90.530 447.130 ;
    END
  END s_axis_tdata[9]
  PIN s_axis_tlast
    DIRECTION INPUT ;
    USE SIGNAL ;
    ANTENNAGATEAREA 0.196500 ;
    PORT
      LAYER met2 ;
        RECT 248.030 443.130 248.310 447.130 ;
    END
  END s_axis_tlast
  PIN s_axis_tready
    DIRECTION OUTPUT ;
    USE SIGNAL ;
    ANTENNADIFFAREA 0.445500 ;
    PORT
      LAYER met2 ;
        RECT 264.130 443.130 264.410 447.130 ;
    END
  END s_axis_tready
  PIN s_axis_tuser
    DIRECTION INPUT ;
    USE SIGNAL ;
    ANTENNAGATEAREA 0.196500 ;
    PORT
      LAYER met2 ;
        RECT 257.690 443.130 257.970 447.130 ;
    END
  END s_axis_tuser
  PIN s_axis_tvalid
    DIRECTION INPUT ;
    USE SIGNAL ;
    ANTENNAGATEAREA 0.196500 ;
    PORT
      LAYER met2 ;
        RECT 260.910 443.130 261.190 447.130 ;
    END
  END s_axis_tvalid
  OBS
      LAYER nwell ;
        RECT 5.330 10.795 430.750 435.285 ;
      LAYER li1 ;
        RECT 5.520 10.795 430.560 435.285 ;
      LAYER met1 ;
        RECT 4.210 10.640 430.560 443.660 ;
      LAYER met2 ;
        RECT 4.230 442.850 15.910 443.770 ;
        RECT 16.750 442.850 19.130 443.770 ;
        RECT 19.970 442.850 22.350 443.770 ;
        RECT 23.190 442.850 25.570 443.770 ;
        RECT 26.410 442.850 28.790 443.770 ;
        RECT 29.630 442.850 32.010 443.770 ;
        RECT 32.850 442.850 35.230 443.770 ;
        RECT 36.070 442.850 38.450 443.770 ;
        RECT 39.290 442.850 41.670 443.770 ;
        RECT 42.510 442.850 44.890 443.770 ;
        RECT 45.730 442.850 48.110 443.770 ;
        RECT 48.950 442.850 51.330 443.770 ;
        RECT 52.170 442.850 54.550 443.770 ;
        RECT 55.390 442.850 57.770 443.770 ;
        RECT 58.610 442.850 60.990 443.770 ;
        RECT 61.830 442.850 64.210 443.770 ;
        RECT 65.050 442.850 67.430 443.770 ;
        RECT 68.270 442.850 70.650 443.770 ;
        RECT 71.490 442.850 73.870 443.770 ;
        RECT 74.710 442.850 77.090 443.770 ;
        RECT 77.930 442.850 80.310 443.770 ;
        RECT 81.150 442.850 83.530 443.770 ;
        RECT 84.370 442.850 86.750 443.770 ;
        RECT 87.590 442.850 89.970 443.770 ;
        RECT 90.810 442.850 93.190 443.770 ;
        RECT 94.030 442.850 96.410 443.770 ;
        RECT 97.250 442.850 99.630 443.770 ;
        RECT 100.470 442.850 102.850 443.770 ;
        RECT 103.690 442.850 106.070 443.770 ;
        RECT 106.910 442.850 109.290 443.770 ;
        RECT 110.130 442.850 112.510 443.770 ;
        RECT 113.350 442.850 115.730 443.770 ;
        RECT 116.570 442.850 118.950 443.770 ;
        RECT 119.790 442.850 122.170 443.770 ;
        RECT 123.010 442.850 125.390 443.770 ;
        RECT 126.230 442.850 128.610 443.770 ;
        RECT 129.450 442.850 131.830 443.770 ;
        RECT 132.670 442.850 135.050 443.770 ;
        RECT 135.890 442.850 138.270 443.770 ;
        RECT 139.110 442.850 141.490 443.770 ;
        RECT 142.330 442.850 144.710 443.770 ;
        RECT 145.550 442.850 147.930 443.770 ;
        RECT 148.770 442.850 151.150 443.770 ;
        RECT 151.990 442.850 154.370 443.770 ;
        RECT 155.210 442.850 157.590 443.770 ;
        RECT 158.430 442.850 160.810 443.770 ;
        RECT 161.650 442.850 164.030 443.770 ;
        RECT 164.870 442.850 167.250 443.770 ;
        RECT 168.090 442.850 170.470 443.770 ;
        RECT 171.310 442.850 173.690 443.770 ;
        RECT 174.530 442.850 176.910 443.770 ;
        RECT 177.750 442.850 180.130 443.770 ;
        RECT 180.970 442.850 183.350 443.770 ;
        RECT 184.190 442.850 186.570 443.770 ;
        RECT 187.410 442.850 189.790 443.770 ;
        RECT 190.630 442.850 193.010 443.770 ;
        RECT 193.850 442.850 196.230 443.770 ;
        RECT 197.070 442.850 199.450 443.770 ;
        RECT 200.290 442.850 202.670 443.770 ;
        RECT 203.510 442.850 205.890 443.770 ;
        RECT 206.730 442.850 209.110 443.770 ;
        RECT 209.950 442.850 212.330 443.770 ;
        RECT 213.170 442.850 215.550 443.770 ;
        RECT 216.390 442.850 218.770 443.770 ;
        RECT 219.610 442.850 221.990 443.770 ;
        RECT 222.830 442.850 225.210 443.770 ;
        RECT 226.050 442.850 228.430 443.770 ;
        RECT 229.270 442.850 231.650 443.770 ;
        RECT 232.490 442.850 234.870 443.770 ;
        RECT 235.710 442.850 238.090 443.770 ;
        RECT 238.930 442.850 241.310 443.770 ;
        RECT 242.150 442.850 244.530 443.770 ;
        RECT 245.370 442.850 247.750 443.770 ;
        RECT 248.590 442.850 250.970 443.770 ;
        RECT 251.810 442.850 254.190 443.770 ;
        RECT 255.030 442.850 257.410 443.770 ;
        RECT 258.250 442.850 260.630 443.770 ;
        RECT 261.470 442.850 263.850 443.770 ;
        RECT 264.690 442.850 267.070 443.770 ;
        RECT 267.910 442.850 270.290 443.770 ;
        RECT 271.130 442.850 273.510 443.770 ;
        RECT 274.350 442.850 276.730 443.770 ;
        RECT 277.570 442.850 279.950 443.770 ;
        RECT 280.790 442.850 283.170 443.770 ;
        RECT 284.010 442.850 286.390 443.770 ;
        RECT 287.230 442.850 289.610 443.770 ;
        RECT 290.450 442.850 292.830 443.770 ;
        RECT 293.670 442.850 296.050 443.770 ;
        RECT 296.890 442.850 299.270 443.770 ;
        RECT 300.110 442.850 302.490 443.770 ;
        RECT 303.330 442.850 305.710 443.770 ;
        RECT 306.550 442.850 308.930 443.770 ;
        RECT 309.770 442.850 312.150 443.770 ;
        RECT 312.990 442.850 315.370 443.770 ;
        RECT 316.210 442.850 318.590 443.770 ;
        RECT 319.430 442.850 321.810 443.770 ;
        RECT 322.650 442.850 325.030 443.770 ;
        RECT 325.870 442.850 328.250 443.770 ;
        RECT 329.090 442.850 331.470 443.770 ;
        RECT 332.310 442.850 334.690 443.770 ;
        RECT 335.530 442.850 337.910 443.770 ;
        RECT 338.750 442.850 341.130 443.770 ;
        RECT 341.970 442.850 344.350 443.770 ;
        RECT 345.190 442.850 347.570 443.770 ;
        RECT 348.410 442.850 350.790 443.770 ;
        RECT 351.630 442.850 354.010 443.770 ;
        RECT 354.850 442.850 357.230 443.770 ;
        RECT 358.070 442.850 360.450 443.770 ;
        RECT 361.290 442.850 363.670 443.770 ;
        RECT 364.510 442.850 366.890 443.770 ;
        RECT 367.730 442.850 370.110 443.770 ;
        RECT 370.950 442.850 373.330 443.770 ;
        RECT 374.170 442.850 376.550 443.770 ;
        RECT 377.390 442.850 379.770 443.770 ;
        RECT 380.610 442.850 382.990 443.770 ;
        RECT 383.830 442.850 386.210 443.770 ;
        RECT 387.050 442.850 389.430 443.770 ;
        RECT 390.270 442.850 392.650 443.770 ;
        RECT 393.490 442.850 395.870 443.770 ;
        RECT 396.710 442.850 399.090 443.770 ;
        RECT 399.930 442.850 402.310 443.770 ;
        RECT 403.150 442.850 405.530 443.770 ;
        RECT 406.370 442.850 408.750 443.770 ;
        RECT 409.590 442.850 430.000 443.770 ;
        RECT 4.230 4.280 430.000 442.850 ;
        RECT 4.230 4.000 6.250 4.280 ;
        RECT 7.090 4.000 9.470 4.280 ;
        RECT 10.310 4.000 12.690 4.280 ;
        RECT 13.530 4.000 15.910 4.280 ;
        RECT 16.750 4.000 19.130 4.280 ;
        RECT 19.970 4.000 22.350 4.280 ;
        RECT 23.190 4.000 25.570 4.280 ;
        RECT 26.410 4.000 28.790 4.280 ;
        RECT 29.630 4.000 32.010 4.280 ;
        RECT 32.850 4.000 35.230 4.280 ;
        RECT 36.070 4.000 38.450 4.280 ;
        RECT 39.290 4.000 41.670 4.280 ;
        RECT 42.510 4.000 44.890 4.280 ;
        RECT 45.730 4.000 48.110 4.280 ;
        RECT 48.950 4.000 51.330 4.280 ;
        RECT 52.170 4.000 54.550 4.280 ;
        RECT 55.390 4.000 57.770 4.280 ;
        RECT 58.610 4.000 60.990 4.280 ;
        RECT 61.830 4.000 64.210 4.280 ;
        RECT 65.050 4.000 67.430 4.280 ;
        RECT 68.270 4.000 70.650 4.280 ;
        RECT 71.490 4.000 73.870 4.280 ;
        RECT 74.710 4.000 77.090 4.280 ;
        RECT 77.930 4.000 80.310 4.280 ;
        RECT 81.150 4.000 83.530 4.280 ;
        RECT 84.370 4.000 86.750 4.280 ;
        RECT 87.590 4.000 89.970 4.280 ;
        RECT 90.810 4.000 93.190 4.280 ;
        RECT 94.030 4.000 96.410 4.280 ;
        RECT 97.250 4.000 99.630 4.280 ;
        RECT 100.470 4.000 102.850 4.280 ;
        RECT 103.690 4.000 106.070 4.280 ;
        RECT 106.910 4.000 109.290 4.280 ;
        RECT 110.130 4.000 318.590 4.280 ;
        RECT 319.430 4.000 321.810 4.280 ;
        RECT 322.650 4.000 376.550 4.280 ;
        RECT 377.390 4.000 408.750 4.280 ;
        RECT 409.590 4.000 411.970 4.280 ;
        RECT 412.810 4.000 415.190 4.280 ;
        RECT 416.030 4.000 418.410 4.280 ;
        RECT 419.250 4.000 430.000 4.280 ;
      LAYER met3 ;
        RECT 4.400 434.840 432.410 435.705 ;
        RECT 3.990 432.840 432.410 434.840 ;
        RECT 4.400 431.440 432.410 432.840 ;
        RECT 3.990 429.440 432.410 431.440 ;
        RECT 4.400 428.040 432.410 429.440 ;
        RECT 3.990 426.040 432.410 428.040 ;
        RECT 4.400 424.640 432.410 426.040 ;
        RECT 3.990 422.640 432.410 424.640 ;
        RECT 4.400 421.240 432.410 422.640 ;
        RECT 3.990 419.240 432.410 421.240 ;
        RECT 4.400 417.840 432.410 419.240 ;
        RECT 3.990 415.840 432.410 417.840 ;
        RECT 4.400 414.440 432.410 415.840 ;
        RECT 3.990 409.040 432.410 414.440 ;
        RECT 4.400 407.640 432.410 409.040 ;
        RECT 3.990 405.640 432.410 407.640 ;
        RECT 4.400 404.240 432.410 405.640 ;
        RECT 3.990 402.240 432.410 404.240 ;
        RECT 4.400 400.840 432.410 402.240 ;
        RECT 3.990 398.840 432.410 400.840 ;
        RECT 4.400 397.440 432.410 398.840 ;
        RECT 3.990 395.440 432.410 397.440 ;
        RECT 4.400 394.040 432.010 395.440 ;
        RECT 3.990 392.040 432.410 394.040 ;
        RECT 4.400 390.640 432.410 392.040 ;
        RECT 3.990 388.640 432.410 390.640 ;
        RECT 4.400 387.240 432.410 388.640 ;
        RECT 3.990 385.240 432.410 387.240 ;
        RECT 4.400 383.840 432.410 385.240 ;
        RECT 3.990 371.640 432.410 383.840 ;
        RECT 3.990 370.240 432.010 371.640 ;
        RECT 3.990 368.240 432.410 370.240 ;
        RECT 3.990 366.840 432.010 368.240 ;
        RECT 3.990 347.840 432.410 366.840 ;
        RECT 3.990 346.440 432.010 347.840 ;
        RECT 3.990 337.640 432.410 346.440 ;
        RECT 3.990 336.240 432.010 337.640 ;
        RECT 3.990 330.840 432.410 336.240 ;
        RECT 3.990 329.440 432.010 330.840 ;
        RECT 3.990 320.640 432.410 329.440 ;
        RECT 3.990 319.240 432.010 320.640 ;
        RECT 3.990 296.840 432.410 319.240 ;
        RECT 3.990 295.440 432.010 296.840 ;
        RECT 3.990 293.440 432.410 295.440 ;
        RECT 3.990 292.040 432.010 293.440 ;
        RECT 3.990 273.040 432.410 292.040 ;
        RECT 3.990 271.640 432.010 273.040 ;
        RECT 3.990 266.240 432.410 271.640 ;
        RECT 3.990 264.840 432.010 266.240 ;
        RECT 3.990 249.240 432.410 264.840 ;
        RECT 3.990 247.840 432.010 249.240 ;
        RECT 3.990 235.640 432.410 247.840 ;
        RECT 3.990 234.240 432.010 235.640 ;
        RECT 3.990 228.840 432.410 234.240 ;
        RECT 3.990 227.440 432.010 228.840 ;
        RECT 3.990 215.240 432.410 227.440 ;
        RECT 3.990 213.840 432.010 215.240 ;
        RECT 3.990 205.040 432.410 213.840 ;
        RECT 3.990 203.640 432.010 205.040 ;
        RECT 3.990 201.640 432.410 203.640 ;
        RECT 3.990 200.240 432.010 201.640 ;
        RECT 3.990 198.240 432.410 200.240 ;
        RECT 3.990 196.840 432.010 198.240 ;
        RECT 3.990 191.440 432.410 196.840 ;
        RECT 3.990 190.040 432.010 191.440 ;
        RECT 3.990 177.840 432.410 190.040 ;
        RECT 3.990 176.440 432.010 177.840 ;
        RECT 3.990 174.440 432.410 176.440 ;
        RECT 3.990 173.040 432.010 174.440 ;
        RECT 3.990 154.040 432.410 173.040 ;
        RECT 3.990 152.640 432.010 154.040 ;
        RECT 3.990 150.640 432.410 152.640 ;
        RECT 3.990 149.240 432.010 150.640 ;
        RECT 3.990 147.240 432.410 149.240 ;
        RECT 3.990 145.840 432.010 147.240 ;
        RECT 3.990 143.840 432.410 145.840 ;
        RECT 3.990 142.440 432.010 143.840 ;
        RECT 3.990 140.440 432.410 142.440 ;
        RECT 3.990 139.040 432.010 140.440 ;
        RECT 3.990 137.040 432.410 139.040 ;
        RECT 3.990 135.640 432.010 137.040 ;
        RECT 3.990 133.640 432.410 135.640 ;
        RECT 3.990 132.240 432.010 133.640 ;
        RECT 3.990 99.640 432.410 132.240 ;
        RECT 4.400 98.240 432.010 99.640 ;
        RECT 3.990 96.240 432.410 98.240 ;
        RECT 3.990 94.840 432.010 96.240 ;
        RECT 3.990 92.840 432.410 94.840 ;
        RECT 3.990 91.440 432.010 92.840 ;
        RECT 3.990 89.440 432.410 91.440 ;
        RECT 3.990 88.040 432.010 89.440 ;
        RECT 3.990 86.040 432.410 88.040 ;
        RECT 3.990 84.640 432.010 86.040 ;
        RECT 3.990 82.640 432.410 84.640 ;
        RECT 3.990 81.240 432.010 82.640 ;
        RECT 3.990 45.240 432.410 81.240 ;
        RECT 3.990 43.840 432.010 45.240 ;
        RECT 3.990 41.840 432.410 43.840 ;
        RECT 3.990 40.440 432.010 41.840 ;
        RECT 3.990 38.440 432.410 40.440 ;
        RECT 3.990 37.040 432.010 38.440 ;
        RECT 3.990 21.440 432.410 37.040 ;
        RECT 3.990 20.040 432.010 21.440 ;
        RECT 3.990 18.040 432.410 20.040 ;
        RECT 3.990 16.640 432.010 18.040 ;
        RECT 3.990 10.715 432.410 16.640 ;
      LAYER met4 ;
        RECT 30.655 72.255 174.240 425.505 ;
        RECT 176.640 72.255 177.540 425.505 ;
        RECT 179.940 72.255 327.840 425.505 ;
        RECT 330.240 72.255 331.140 425.505 ;
        RECT 333.540 72.255 427.505 425.505 ;
  END
END gelu_top
END LIBRARY

